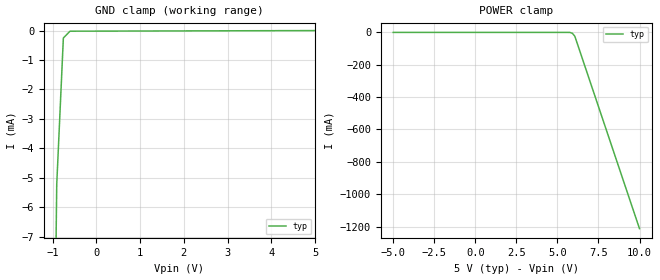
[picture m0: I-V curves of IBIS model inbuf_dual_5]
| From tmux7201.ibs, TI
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| inbuf_dual_5
[Model]   inbuf_dual_5
Model_type   Input
Vinl = 0.8
Vinh = 1.3
|   typ   min   max
C_comp   4.014581e-13   NA   NA
[Voltage Range]   5   NA   NA
[Temperature Range]   27   NA   NA
[Power Clamp Reference]   5   NA   NA
[GND Clamp Reference]   0   NA   NA
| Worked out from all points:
|   GND clamp passes 1 mA (typ) near -0.78 V on its own axis
[GND Clamp]
|   Voltage   I(typ)   I(min)   I(max)
-10V      -2.791A    NA         NA
-1.061V   -23.61mA   NA         NA
-909.1mV  -5.222mA   NA         NA
-757.6mV  -252.5uA   NA         NA
-606.1mV  -20.16uA   NA         NA
5V        554.6nA    NA         NA
[POWER Clamp]
|   Voltage   I(typ)   I(min)   I(max)
-5V       554.8nA    NA         NA
5.606V    -20.16uA   NA         NA
5.758V    -252.5uA   NA         NA
5.909V    -5.222mA   NA         NA
6.061V    -23.61mA   NA         NA
10V       -1.213A    NA         NA
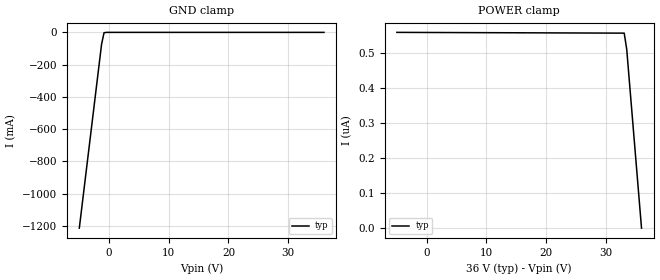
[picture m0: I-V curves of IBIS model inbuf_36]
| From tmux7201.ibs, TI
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| inbuf_36
[Model]   inbuf_36
Model_type   Input
Vinl = 0.8
Vinh = 1.3
|   typ   min   max
C_comp   4.014581e-13   NA   NA
[Voltage Range]   36   NA   NA
[Temperature Range]   27   NA   NA
[Power Clamp Reference]   36   NA   NA
[GND Clamp Reference]   0   NA   NA
[GND Clamp]
|   Voltage   I(typ)   I(min)   I(max)
-5V       -1.213A    NA         NA
-1.273V   -74.84mA   NA         NA
-858.6mV  -2.445mA   NA         NA
-444.4mV  -3.245uA   NA         NA
36V       559.4nA    NA         NA
[POWER Clamp]
|   Voltage   I(typ)   I(min)   I(max)
-5V       559.6nA    NA         NA
33.1V     557.4nA    NA         NA
33.52V    511.4nA    NA         NA
36V       -196.7pA   NA         NA
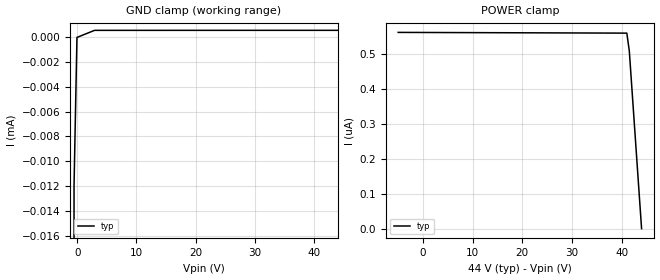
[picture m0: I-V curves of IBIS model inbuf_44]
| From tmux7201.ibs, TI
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| inbuf_44
[Model]   inbuf_44
Model_type   Input
Vinl = 0.8
Vinh = 1.3
|   typ   min   max
C_comp   2.533030e-13   NA   NA
[Voltage Range]   44   NA   NA
[Temperature Range]   27   NA   NA
[Power Clamp Reference]   44   NA   NA
[GND Clamp Reference]   0   NA   NA
[GND Clamp]
|   Voltage   I(typ)   I(min)   I(max)
-5V       -1.213A    NA         NA
-1.04V    -19.95mA   NA         NA
-545.5mV  -12.01uA   NA         NA
-50.51mV  -10.67nA   NA         NA
2.919V    560.4nA    NA         NA
44V       562.6nA    NA         NA
[POWER Clamp]
|   Voltage   I(typ)   I(min)   I(max)
-5V       562.8nA    NA         NA
41.03V    560.7nA    NA         NA
41.53V    509.4nA    NA         NA
44V       -236.9pA   NA         NA
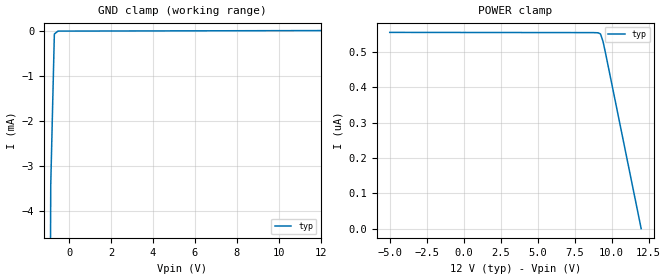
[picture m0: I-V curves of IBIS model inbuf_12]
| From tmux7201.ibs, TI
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| inbuf_12
[Model]   inbuf_12
Model_type   Input
Vinl = 0.8
Vinh = 1.3
|   typ   min   max
C_comp   4.014581e-13   NA   NA
[Voltage Range]   12   NA   NA
[Temperature Range]   27   NA   NA
[Power Clamp Reference]   12   NA   NA
[GND Clamp Reference]   0   NA   NA
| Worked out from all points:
|   GND clamp passes 1 mA (typ) near -0.75 V on its own axis
[GND Clamp]
|   Voltage   I(typ)   I(min)   I(max)
-5V       -1.213A    NA         NA
-1.051V   -21.74mA   NA         NA
-878.8mV  -3.405mA   NA         NA
-707.1mV  -75.01uA   NA         NA
-535.4mV  -10.89uA   NA         NA
12V       554.9nA    NA         NA
[POWER Clamp]
|   Voltage   I(typ)   I(min)   I(max)
-5V       555nA      NA         NA
8.737V    554.4nA    NA         NA
9.081V    553.9nA    NA         NA
9.253V    550.5nA    NA         NA
9.424V    528.7nA    NA         NA
9.596V    495.2nA    NA         NA
12V       -76.08pA   NA         NA
